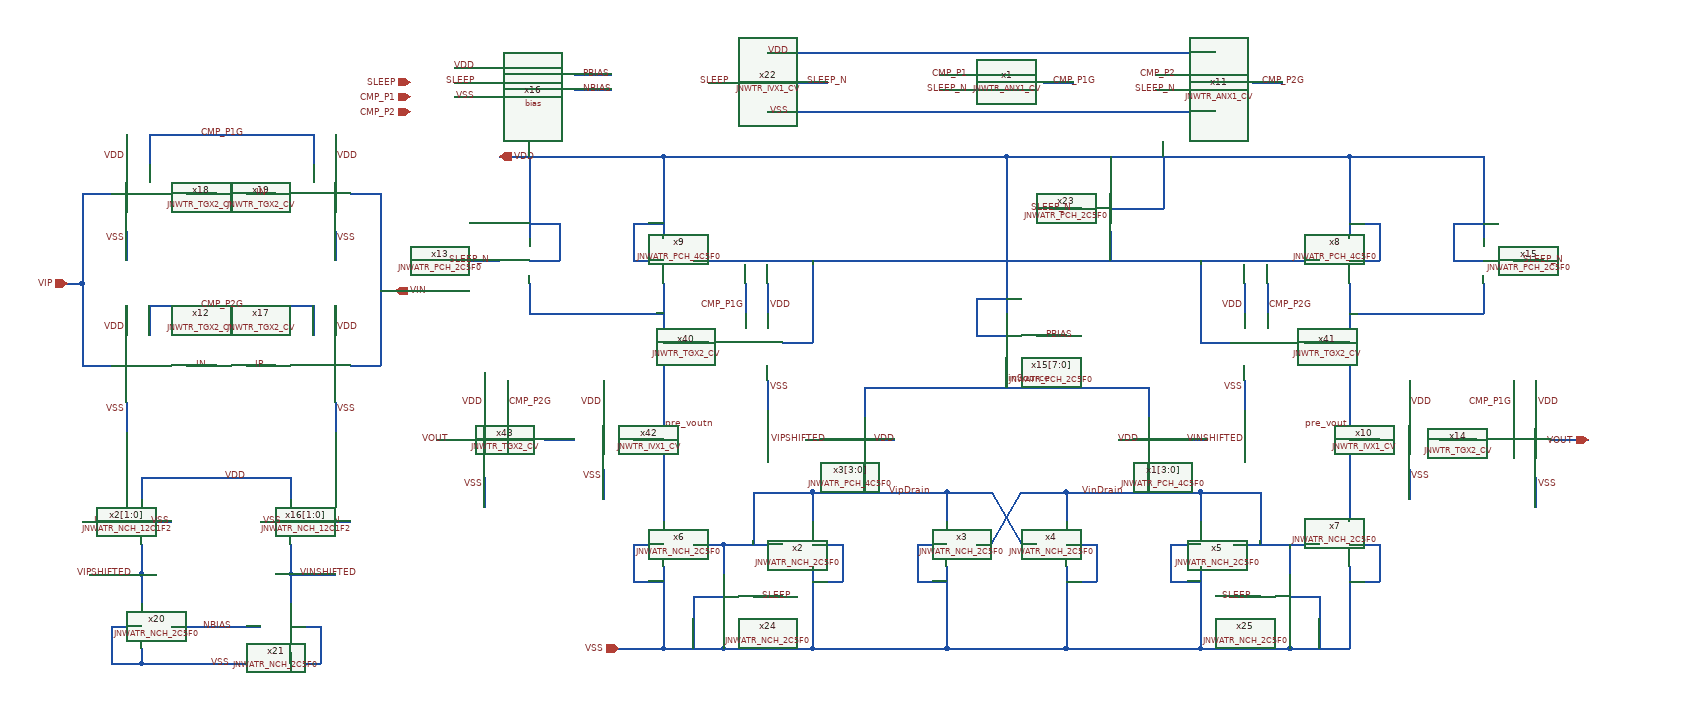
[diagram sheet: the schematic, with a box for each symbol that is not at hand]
v {xschem version=3.4.6 file_version=1.2}
G {}
K {}
V {}
S {}
E {}
N 1340 780 1340 820 {
lab=VipDrain}
N 1520 780 1520 820 {
lab=VipDrain}
N 1680 780 1680 820 {
lab=VinDrain}
N 1780 780 1860 780 {
lab=VinDrain}
N 1560 850 1580 850 {
lab=VinDrain}
N 1580 850 1620 780 {
lab=VinDrain}
N 1620 850 1640 850 {
lab=VipDrain}
N 1580 780 1620 850 {
lab=VipDrain}
N 1520 780 1580 780 {
lab=VipDrain}
N 1620 780 1680 780 {
lab=VinDrain}
N 1260 780 1340 780 {
lab=VipDrain}
N 1260 780 1260 850 {
lab=VipDrain}
N 1340 470 1340 580 {
lab=#net1}
N 1830 330 2060 330 {
lab=VDD}
N 1980 990 2060 990 {
lab=VSS}
N 1410 640 1410 680 {
lab=inSource}
N 1790 640 1790 680 {
lab=inSource}
N 2280 630 2280 670 {
lab=CMP_P1G}
N 2330 710 2380 710 {
lab=VOUT}
N 360 500 360 610 {
lab=VIP}
N 360 380 400 380 {
lab=VIP}
N 360 610 400 610 {
lab=VIP}
N 760 380 760 610 {
lab=VIN}
N 720 380 760 380 {
lab=VIN}
N 720 610 760 610 {
lab=VIN}
N 450 530 450 570 {
lab=CMP_P2G}
N 450 530 670 530 {
lab=CMP_P2G}
N 670 530 670 570 {
lab=CMP_P2G}
N 450 300 450 340 {
lab=CMP_P1G}
N 450 300 670 300 {
lab=CMP_P1G}
N 670 300 670 340 {
lab=CMP_P1G}
N 1330 710 1370 710 {lab=VIPSHIFTED}
N 360 380 360 500 {
lab=VIP}
N 1830 710 1870 710 {lab=VINSHIFTED}
N 1680 780 1780 780 {
lab=VinDrain}
N 1340 780 1520 780 {
lab=VipDrain}
N 1640 570 1680 570 {lab=PBIAS}
N 1600 600 1600 640 {lab=inSource}
N 360 820 400 820 {lab=IP}
N 1410 640 1790 640 {
lab=inSource}
N 440 760 640 760 {lab=VDD}
N 440 760 440 790 {lab=VDD}
N 640 760 640 790 {lab=VDD}
N 480 960 600 960 {lab=NBIAS}
N 680 820 720 820 {lab=IN}
N 680 960 680 1010 {lab=VSS}
N 440 1010 680 1010 {lab=VSS}
N 400 960 400 1010 {lab=VSS}
N 370 890 440 890 {lab=VIPSHIFTED}
N 640 890 700 890 {lab=VINSHIFTED}
N 640 850 640 890 {lab=VINSHIFTED}
N 440 850 440 890 {lab=VIPSHIFTED}
N 640 890 640 930 {lab=VINSHIFTED}
N 440 890 440 930 {lab=VIPSHIFTED}
N 340 500 360 500 {lab=VIP}
N 1200 230 1240 230 {lab=SLEEP}
N 1320 230 1360 230 {lab=SLEEP_N}
N 1740 430 1740 470 {lab=#net1}
N 1180 470 2020 470 {
lab=#net1}
N 1220 850 1220 890 {lab=VipDrain}
N 1180 850 1220 850 {
lab=VipDrain}
N 1980 850 1980 890 {lab=VinDrain}
N 580 610 620 610 {lab=IP}
N 580 380 620 380 {lab=IN}
N 2180 710 2230 710 {lab=#net2}
N 1860 470 1860 580 {lab=#net1}
N 1300 580 1340 580 {
lab=#net1}
N 1250 500 1250 540 {
lab=CMP_P1G}
N 1949.614593087707 500 1949.614593087707 540 {
lab=CMP_P2G}
N 1140 580 1200 580 {lab=pre_voutn}
N 2000 580 2060 580 {lab=pre_vout}
N 1860 580 1900 580 {lab=#net1}
N 980 710 1020 710 {
lab=#net3}
N 930 630 930 690 {
lab=CMP_P2G}
N 835 710 880 710 {
lab=VOUT}
N 1100 710 1140 710 {lab=pre_voutn}
N 1140 330 1600 330 {
lab=VDD}
N 1600 330 1600 540 {lab=VDD}
N 1140 330 1140 440 {lab=VDD}
N 920 330 1140 330 {
lab=VDD}
N 2060 710 2100 710 {lab=pre_vout}
N 1100 850 1100 900 {lab=VSS}
N 1080 990 1140 990 {
lab=VSS}
N 1140 990 1220 990 {
lab=VSS}
N 1180 920 1180 990 {lab=VSS}
N 1220 990 1340 990 {
lab=VSS}
N 1340 880 1340 990 {lab=VSS}
N 1520 880 1520 990 {lab=VSS}
N 1340 990 1520 990 {
lab=VSS}
N 1520 990 1680 990 {
lab=VSS}
N 1860 880 1860 990 {lab=VSS}
N 1680 990 1860 990 {
lab=VSS}
N 1860 990 1980 990 {
lab=VSS}
N 2020 920 2020 990 {lab=VSS}
N 2060 880 2060 990 {lab=VSS}
N 1810 330 1810 400 {lab=VDD}
N 1740 330 1740 370 {lab=VDD}
N 1600 330 1830 330 {
lab=VDD}
N 1930 230 1970 230 {lab=CMP_P2G}
N 1650 230 1690 230 {lab=CMP_P1G}
N 1510 220 1560 220 {lab=CMP_P1}
N 1510 240 1560 240 {lab=SLEEP_N}
N 1800 240 1840 240 {lab=SLEEP_N}
N 1800 220 1840 220 {lab=CMP_P2}
N 1280 190 1880 190 {lab=VDD}
N 1280 270 1880 270 {lab=VSS}
N 2060 470 2100 470 {lab=VDD}
N 2060 330 2060 440 {lab=VDD}
N 2060 420 2100 420 {lab=VDD}
N 2060 540 2240 540 {lab=pre_vout}
N 1740 400 1810 400 {lab=VDD}
N 500 380 540 380 {lab=IP}
N 500 610 540 610 {lab=IN}
N 420 430 420 470 {lab=VSS}
N 420 300 420 340 {lab=VDD}
N 420 660 420 700 {lab=VSS}
N 420 530 420 570 {lab=VDD}
N 700 430 700 470 {lab=VSS}
N 700 300 700 340 {lab=VDD}
N 700 660 700 700 {lab=VSS}
N 700 530 700 570 {lab=VDD}
N 760 510 780 510 {lab=VIN}
N 400 960 440 960 {lab=VSS}
N 440 990 440 1010 {lab=VSS}
N 640 960 680 960 {lab=VSS}
N 640 995 640 1010 {lab=VSS}
N 440 820 480 820 {lab=VSS}
N 600 820 640 820 {lab=VSS}
N 900 620 900 670 {lab=VDD}
N 900 760 900 800 {lab=VSS}
N 1060 630 1060 670 {lab=VDD}
N 1060 750 1060 790 {lab=VSS}
N 960 500 960 540 {lab=pre_voutn}
N 960 540 1140 540 {lab=pre_voutn}
N 960 330 960 440 {lab=VDD}
N 1100 420 1140 420 {lab=VDD}
N 1100 420 1100 470 {lab=VDD}
N 1100 470 1140 470 {lab=VDD}
N 2240 500 2240 540 {lab=pre_vout}
N 2240 330 2240 440 {lab=VDD}
N 2100 420 2100 470 {lab=VDD}
N 1280 500 1280 540 {lab=VDD}
N 1280 630 1280 670 {lab=VSS}
N 1919.614593087707 500 1919.614593087707 540 {lab=VDD}
N 1919.614593087707 630 1919.614593087707 670 {lab=VSS}
N 880 470 920 470 {lab=SLEEP_N}
N 1560 570 1600 570 {lab=VDD}
N 1560 520 1560 570 {lab=VDD}
N 1560 520 1600 520 {lab=VDD}
N 2310 760 2310 800 {lab=VSS}
N 2310 630 2310 670 {lab=VDD}
N 2140 630 2140 670 {lab=VDD}
N 2140 750 2140 790 {lab=VSS}
N 2280 470 2320 470 {lab=SLEEP_N}
N 1660 400 1700 400 {lab=SLEEP_N}
N 1980 920 2020 920 {lab=VSS}
N 1980 950 1980 990 {lab=VSS}
N 1180 920 1220 920 {lab=VSS}
N 1220 950 1220 990 {lab=VSS}
N 1340 850 1380 850 {lab=VSS}
N 1380 850 1380 900 {lab=VSS}
N 1340 900 1380 900 {lab=VSS}
N 1480 900 1520 900 {lab=VSS}
N 1480 850 1480 900 {lab=VSS}
N 1480 850 1520 850 {lab=VSS}
N 1680 900 1720 900 {lab=VSS}
N 1720 850 1720 900 {lab=VSS}
N 1680 850 1720 850 {lab=VSS}
N 1860 780 1860 820 {lab=VinDrain}
N 1820 850 1860 850 {lab=VSS}
N 1820 850 1820 900 {lab=VSS}
N 1820 900 1860 900 {lab=VSS}
N 1905 850 2020 850 {lab=VinDrain}
N 1220 850 1300 850 {lab=VipDrain}
N 1860 780 1940 780 {lab=VinDrain}
N 1940 780 1940 850 {lab=VinDrain}
N 1410 740 1410 780 {lab=VipDrain}
N 1790 740 1790 780 {lab=VinDrain}
N 1100 850 1140 850 {lab=VSS}
N 1140 880 1140 990 {lab=VSS}
N 1900 920 1940 920 {lab=SLEEP}
N 1260 920 1300 920 {lab=SLEEP}
N 1410 710 1450 710 {lab=VDD}
N 1750 710 1790 710 {lab=VDD}
N 2060 500 2060 820 {lab=pre_vout}
N 1140 500 1140 820 {lab=pre_voutn}
N 2060 850 2100 850 {lab=VSS}
N 2100 850 2100 900 {lab=VSS}
N 2060 900 2100 900 {lab=VSS}
N 1100 900 1140 900 {lab=VSS}
N 2060 330 2240 330 {lab=VDD}
N 2200 470 2240 470 {lab=VDD}
N 2200 420 2200 470 {lab=VDD}
N 2200 420 2240 420 {lab=VDD}
N 960 470 1000 470 {lab=VDD}
N 1000 420 1000 470 {lab=VDD}
N 960 420 1000 420 {lab=VDD}
N 1680 880 1680 990 {lab=VSS}
N 400 1010 440 1010 {lab=VSS}
N 1020 220 1070 220 {lab=PBIAS}
N 1020 240 1070 240 {lab=NBIAS}
N 860 210 900 210 {lab=VDD}
N 860 230 900 230 {lab=SLEEP}
N 860 250 900 250 {lab=VSS}
C {devices/ipin.sym} 1080 990 0 0 {name=p2 lab=VSS
}
C {devices/ipin.sym} 920 330 2 1 {name=p3 lab=VDD
}
C {devices/ipin.sym} 780 510 0 1 {name=p5 lab=VIN
}
C {devices/ipin.sym} 340 500 0 0 {name=p6 lab=VIP
}
C {JNW_ATR_SKY130A/JNWATR_NCH_2C5F0.sym} 1300 850 0 0 {name=x2 }
C {JNW_ATR_SKY130A/JNWATR_NCH_2C5F0.sym} 1560 850 0 1 {name=x3 }
C {JNW_ATR_SKY130A/JNWATR_NCH_2C5F0.sym} 1640 850 0 0 {name=x4 }
C {JNW_ATR_SKY130A/JNWATR_NCH_2C5F0.sym} 1900 850 0 1 {name=x5 }
C {JNW_ATR_SKY130A/JNWATR_NCH_2C5F0.sym} 1180 850 0 1 {name=x6 }
C {JNW_ATR_SKY130A/JNWATR_NCH_2C5F0.sym} 2020 850 0 0 {name=x7 }
C {JNW_ATR_SKY130A/JNWATR_PCH_4C5F0.sym} 2020 470 0 0 {name=x8 }
C {JNW_ATR_SKY130A/JNWATR_PCH_4C5F0.sym} 1180 470 0 1 {name=x9 }
C {devices/opin.sym} 2380 710 2 1 {name=p7 lab=VOUT}
C {JNW_TR_SKY130A/JNWTR_IVX1_CV.sym} 2100 710 0 0 {name=x10 }
C {devices/ipin.sym} 800 270 0 0 {name=p10 lab=CMP_P2
}
C {devices/lab_wire.sym} 2140 760 2 0 {name=p19 sig_type=std_logic lab=VSS}
C {JNW_TR_SKY130A/JNWTR_TGX2_CV.sym} 2220 710 0 0 {name=x14 }
C {devices/lab_wire.sym} 2310 660 0 1 {name=p20 sig_type=std_logic lab=VDD}
C {devices/lab_wire.sym} 2310 770 2 0 {name=p21 sig_type=std_logic lab=VSS}
C {devices/lab_wire.sym} 510 610 0 1 {name=p32 sig_type=std_logic lab=IN}
C {devices/lab_wire.sym} 510 380 0 1 {name=p33 sig_type=std_logic lab=IP}
C {devices/lab_wire.sym} 390 820 0 0 {name=p34 sig_type=std_logic lab=IP}
C {devices/lab_wire.sym} 690 820 0 1 {name=p35 sig_type=std_logic lab=IN}
C {devices/ipin.sym} 800 250 0 0 {name=p11 lab=CMP_P1
}
C {devices/lab_wire.sym} 1760 780 0 0 {name=p12 sig_type=std_logic lab=VinDrain}
C {devices/lab_wire.sym} 1440 780 0 1 {name=p13 sig_type=std_logic lab=VipDrain}
C {devices/lab_wire.sym} 1140 690 0 1 {name=p37 sig_type=std_logic lab=pre_voutn}
C {devices/lab_wire.sym} 2060 690 0 0 {name=p38 sig_type=std_logic lab=pre_vout}
C {JNW_TR_SKY130A/JNWTR_TGX2_CV.sym} 510 610 0 1 {name=x12 }
C {devices/lab_wire.sym} 420 560 0 0 {name=p29 sig_type=std_logic lab=VDD}
C {devices/lab_wire.sym} 420 670 2 1 {name=p30 sig_type=std_logic lab=VSS}
C {JNW_TR_SKY130A/JNWTR_TGX2_CV.sym} 610 610 0 0 {name=x17 }
C {devices/lab_wire.sym} 700 560 0 1 {name=p31 sig_type=std_logic lab=VDD}
C {devices/lab_wire.sym} 700 670 2 0 {name=p36 sig_type=std_logic lab=VSS}
C {JNW_TR_SKY130A/JNWTR_TGX2_CV.sym} 510 380 0 1 {name=x18 }
C {devices/lab_wire.sym} 420 330 0 0 {name=p39 sig_type=std_logic lab=VDD}
C {devices/lab_wire.sym} 420 440 2 1 {name=p40 sig_type=std_logic lab=VSS}
C {JNW_TR_SKY130A/JNWTR_TGX2_CV.sym} 610 380 0 0 {name=x19 }
C {devices/lab_wire.sym} 700 330 0 1 {name=p41 sig_type=std_logic lab=VDD}
C {devices/lab_wire.sym} 700 440 2 0 {name=p42 sig_type=std_logic lab=VSS}
C {devices/lab_wire.sym} 590 610 0 1 {name=p43 sig_type=std_logic lab=IP}
C {devices/lab_wire.sym} 610 380 0 0 {name=p44 sig_type=std_logic lab=IN}
C {JNW_ATR_SKY130A/JNWATR_PCH_2C5F0.sym} 1640 570 0 1 {name=x15[7:0]}
C {devices/lab_wire.sym} 1600 630 0 1 {name=p47 sig_type=std_logic lab=inSource}
C {devices/lab_wire.sym} 2140 660 0 1 {name=p48 sig_type=std_logic lab=VDD}
C {devices/lab_wire.sym} 1650 570 0 1 {name=p23 sig_type=std_logic lab=PBIAS}
C {JNW_ATR_SKY130A/JNWATR_NCH_12C1F2.sym} 400 820 0 0 {name=x2[1:0]}
C {JNW_ATR_SKY130A/JNWATR_NCH_12C1F2.sym} 680 820 0 1 {name=x16[1:0]}
C {devices/lab_wire.sym} 630 820 0 0 {name=p14 sig_type=std_logic lab=VSS}
C {devices/lab_wire.sym} 450 820 0 1 {name=p15 sig_type=std_logic lab=VSS}
C {JNW_ATR_SKY130A/JNWATR_PCH_4C5F0.sym} 1370 710 0 0 {name=x3[3:0]}
C {devices/lab_wire.sym} 1420 710 0 1 {name=p4 sig_type=std_logic lab=VDD}
C {devices/lab_wire.sym} 550 760 0 1 {name=p16 sig_type=std_logic lab=VDD}
C {JNW_ATR_SKY130A/JNWATR_NCH_2C5F0.sym} 480 960 0 1 {name=x20 }
C {JNW_ATR_SKY130A/JNWATR_NCH_2C5F0.sym} 600 960 0 0 {name=x21 }
C {devices/lab_wire.sym} 530 1010 0 1 {name=p17 sig_type=std_logic lab=VSS}
C {devices/lab_wire.sym} 520 960 0 1 {name=p24 sig_type=std_logic lab=NBIAS}
C {devices/lab_wire.sym} 430 890 0 0 {name=p25 sig_type=std_logic lab=VIPSHIFTED}
C {devices/lab_wire.sym} 650 890 0 1 {name=p26 sig_type=std_logic lab=VINSHIFTED}
C {JNW_ATR_SKY130A/JNWATR_PCH_4C5F0.sym} 1830 710 0 1 {name=x1[3:0]}
C {JNW_TR_SKY130A/JNWTR_IVX1_CV.sym} 1240 230 0 0 {name=x22 }
C {devices/lab_wire.sym} 1330 230 0 1 {name=p50 sig_type=std_logic lab=SLEEP_N}
C {devices/lab_wire.sym} 1230 230 0 0 {name=p55 sig_type=std_logic lab=SLEEP}
C {devices/lab_wire.sym} 1310 270 2 1 {name=p56 sig_type=std_logic lab=VSS}
C {devices/lab_wire.sym} 1310 190 0 0 {name=p57 sig_type=std_logic lab=VDD}
C {JNW_ATR_SKY130A/JNWATR_PCH_2C5F0.sym} 1700 400 0 0 {name=x23 }
C {devices/lab_wire.sym} 1690 400 0 0 {name=p58 sig_type=std_logic lab=SLEEP_N}
C {JNW_ATR_SKY130A/JNWATR_NCH_2C5F0.sym} 1260 920 0 1 {name=x24 }
C {devices/lab_wire.sym} 1270 920 0 1 {name=p59 sig_type=std_logic lab=SLEEP}
C {JNW_ATR_SKY130A/JNWATR_NCH_2C5F0.sym} 1940 920 0 0 {name=x25 }
C {devices/lab_wire.sym} 1930 920 0 0 {name=p60 sig_type=std_logic lab=SLEEP}
C {devices/ipin.sym} 800 230 0 0 {name=p61 lab=SLEEP
}
C {JNW_TR_SKY130A/JNWTR_TGX2_CV.sym} 1190 580 0 0 {name=x40 }
C {devices/lab_wire.sym} 1280 640 2 0 {name=p66 sig_type=std_logic lab=VSS}
C {JNW_TR_SKY130A/JNWTR_TGX2_CV.sym} 2009.614593087707 580 0 1 {name=x41 }
C {devices/lab_wire.sym} 1919.614593087707 530 0 0 {name=p88 sig_type=std_logic lab=VDD}
C {devices/lab_wire.sym} 1919.614593087707 640 2 1 {name=p96 sig_type=std_logic lab=VSS}
C {JNW_TR_SKY130A/JNWTR_IVX1_CV.sym} 1100 710 0 1 {name=x42 }
C {devices/lab_wire.sym} 1060 660 0 0 {name=p98 sig_type=std_logic lab=VDD}
C {devices/lab_wire.sym} 1060 760 2 1 {name=p99 sig_type=std_logic lab=VSS}
C {JNW_TR_SKY130A/JNWTR_TGX2_CV.sym} 990 710 0 1 {name=x43 }
C {devices/lab_wire.sym} 900 660 0 0 {name=p100 sig_type=std_logic lab=VDD}
C {devices/lab_wire.sym} 900 770 2 1 {name=p101 sig_type=std_logic lab=VSS}
C {devices/lab_wire.sym} 855 710 0 0 {name=p103 sig_type=std_logic lab=VOUT}
C {JNW_TR_SKY130A/JNWTR_ANX1_CV.sym} 1560 240 0 0 {name=x1 }
C {JNW_TR_SKY130A/JNWTR_ANX1_CV.sym} 1840 240 0 0 {name=x11 }
C {devices/lab_wire.sym} 1550 240 0 0 {name=p18 sig_type=std_logic lab=SLEEP_N}
C {devices/lab_wire.sym} 1830 240 0 0 {name=p49 sig_type=std_logic lab=SLEEP_N}
C {devices/lab_wire.sym} 1550 220 0 0 {name=p51 sig_type=std_logic lab=CMP_P1}
C {devices/lab_wire.sym} 1830 220 0 0 {name=p52 sig_type=std_logic lab=CMP_P2}
C {devices/lab_wire.sym} 1940 230 0 1 {name=p53 sig_type=std_logic lab=CMP_P2G}
C {devices/lab_wire.sym} 1660 230 0 1 {name=p54 sig_type=std_logic lab=CMP_P1G}
C {devices/lab_wire.sym} 930 660 0 1 {name=p46 sig_type=std_logic lab=CMP_P2G}
C {devices/lab_wire.sym} 1949.614593087707 530 0 1 {name=p62 sig_type=std_logic lab=CMP_P2G}
C {devices/lab_wire.sym} 1250 530 0 0 {name=p64 sig_type=std_logic lab=CMP_P1G}
C {devices/lab_wire.sym} 2280 660 0 0 {name=p22 sig_type=std_logic lab=CMP_P1G}
C {JNW_ATR_SKY130A/JNWATR_PCH_2C5F0.sym} 920 470 0 0 {name=x13 }
C {JNW_ATR_SKY130A/JNWATR_PCH_2C5F0.sym} 2280 470 0 1 {name=x15 }
C {devices/lab_wire.sym} 910 470 0 0 {name=p67 sig_type=std_logic lab=SLEEP_N}
C {devices/lab_wire.sym} 2290 470 0 1 {name=p68 sig_type=std_logic lab=SLEEP_N}
C {devices/lab_wire.sym} 580 530 0 0 {name=p69 sig_type=std_logic lab=CMP_P2G}
C {devices/lab_wire.sym} 580 300 0 0 {name=p70 sig_type=std_logic lab=CMP_P1G}
C {devices/lab_wire.sym} 1280 530 0 1 {name=p45 sig_type=std_logic lab=VDD}
C {devices/lab_wire.sym} 1780 710 0 0 {name=p8 sig_type=std_logic lab=VDD}
C {LELO_TORD_SKY130A/bias.sym} 960 230 0 0 {name=x16}
C {devices/lab_wire.sym} 1030 220 0 1 {name=p1 sig_type=std_logic lab=PBIAS}
C {devices/lab_wire.sym} 1030 240 0 1 {name=p9 sig_type=std_logic lab=NBIAS}
C {devices/lab_wire.sym} 890 210 0 0 {name=p63 sig_type=std_logic lab=VDD}
C {devices/lab_wire.sym} 890 230 0 0 {name=p65 sig_type=std_logic lab=SLEEP}
C {devices/lab_wire.sym} 890 250 0 0 {name=p71 sig_type=std_logic lab=VSS}
C {devices/lab_wire.sym} 1840 710 0 1 {name=p72 sig_type=std_logic lab=VINSHIFTED}
C {devices/lab_wire.sym} 1360 710 0 0 {name=p27 sig_type=std_logic lab=VIPSHIFTED}
